VERSION 5.7 ;
  DIVIDERCHAR "/" ;
  BUSBITCHARS "[]" ;
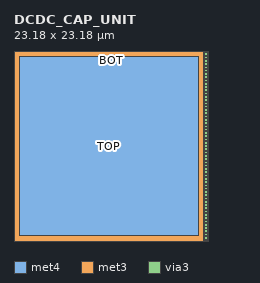
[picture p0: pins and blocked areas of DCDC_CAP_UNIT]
MACRO DCDC_CAP_UNIT
  CLASS BLOCK ;
  FOREIGN DCDC_CAP_UNIT ;
  ORIGIN 0.000 0.000 ;
  SIZE 23.180 BY 23.180 ;
  PIN TOP
    PORT
      LAYER met4 ;
        RECT 0.695 0.695 22.485 22.485 ;
    END
  END TOP
  PIN BOT
    PORT
      LAYER met3 ;
        RECT 0.000 0.000 23.675 23.180 ;
      LAYER via3 ;
        RECT 23.255 22.630 23.575 22.950 ;
        RECT 23.255 22.230 23.575 22.550 ;
        RECT 23.255 21.830 23.575 22.150 ;
        RECT 23.255 21.430 23.575 21.750 ;
        RECT 23.255 21.030 23.575 21.350 ;
        RECT 23.255 20.630 23.575 20.950 ;
        RECT 23.255 20.230 23.575 20.550 ;
        RECT 23.255 19.830 23.575 20.150 ;
        RECT 23.255 19.430 23.575 19.750 ;
        RECT 23.255 19.030 23.575 19.350 ;
        RECT 23.255 18.630 23.575 18.950 ;
        RECT 23.255 18.230 23.575 18.550 ;
        RECT 23.255 17.830 23.575 18.150 ;
        RECT 23.255 17.430 23.575 17.750 ;
        RECT 23.255 17.030 23.575 17.350 ;
        RECT 23.255 16.630 23.575 16.950 ;
        RECT 23.255 16.230 23.575 16.550 ;
        RECT 23.255 15.830 23.575 16.150 ;
        RECT 23.255 15.430 23.575 15.750 ;
        RECT 23.255 15.030 23.575 15.350 ;
        RECT 23.255 14.630 23.575 14.950 ;
        RECT 23.255 14.230 23.575 14.550 ;
        RECT 23.255 13.830 23.575 14.150 ;
        RECT 23.255 13.430 23.575 13.750 ;
        RECT 23.255 13.030 23.575 13.350 ;
        RECT 23.255 12.630 23.575 12.950 ;
        RECT 23.255 12.230 23.575 12.550 ;
        RECT 23.255 11.830 23.575 12.150 ;
        RECT 23.255 11.430 23.575 11.750 ;
        RECT 23.255 11.030 23.575 11.350 ;
        RECT 23.255 10.630 23.575 10.950 ;
        RECT 23.255 10.230 23.575 10.550 ;
        RECT 23.255 9.830 23.575 10.150 ;
        RECT 23.255 9.430 23.575 9.750 ;
        RECT 23.255 9.030 23.575 9.350 ;
        RECT 23.255 8.630 23.575 8.950 ;
        RECT 23.255 8.230 23.575 8.550 ;
        RECT 23.255 7.830 23.575 8.150 ;
        RECT 23.255 7.430 23.575 7.750 ;
        RECT 23.255 7.030 23.575 7.350 ;
        RECT 23.255 6.630 23.575 6.950 ;
        RECT 23.255 6.230 23.575 6.550 ;
        RECT 23.255 5.830 23.575 6.150 ;
        RECT 23.255 5.430 23.575 5.750 ;
        RECT 23.255 5.030 23.575 5.350 ;
        RECT 23.255 4.630 23.575 4.950 ;
        RECT 23.255 4.230 23.575 4.550 ;
        RECT 23.255 3.830 23.575 4.150 ;
        RECT 23.255 3.430 23.575 3.750 ;
        RECT 23.255 3.030 23.575 3.350 ;
        RECT 23.255 2.630 23.575 2.950 ;
        RECT 23.255 2.230 23.575 2.550 ;
        RECT 23.255 1.830 23.575 2.150 ;
        RECT 23.255 1.430 23.575 1.750 ;
        RECT 23.255 1.030 23.575 1.350 ;
        RECT 23.255 0.630 23.575 0.950 ;
        RECT 23.255 0.230 23.575 0.550 ;
      LAYER met4 ;
        RECT 23.175 0.060 23.655 23.120 ;
    END
  END BOT
END DCDC_CAP_UNIT
END LIBRARY

